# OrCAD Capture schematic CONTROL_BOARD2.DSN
size A4; title: CONTROL BOARD2; rev: 1.0; note: ELECTRONIC CAD 2024.06.03

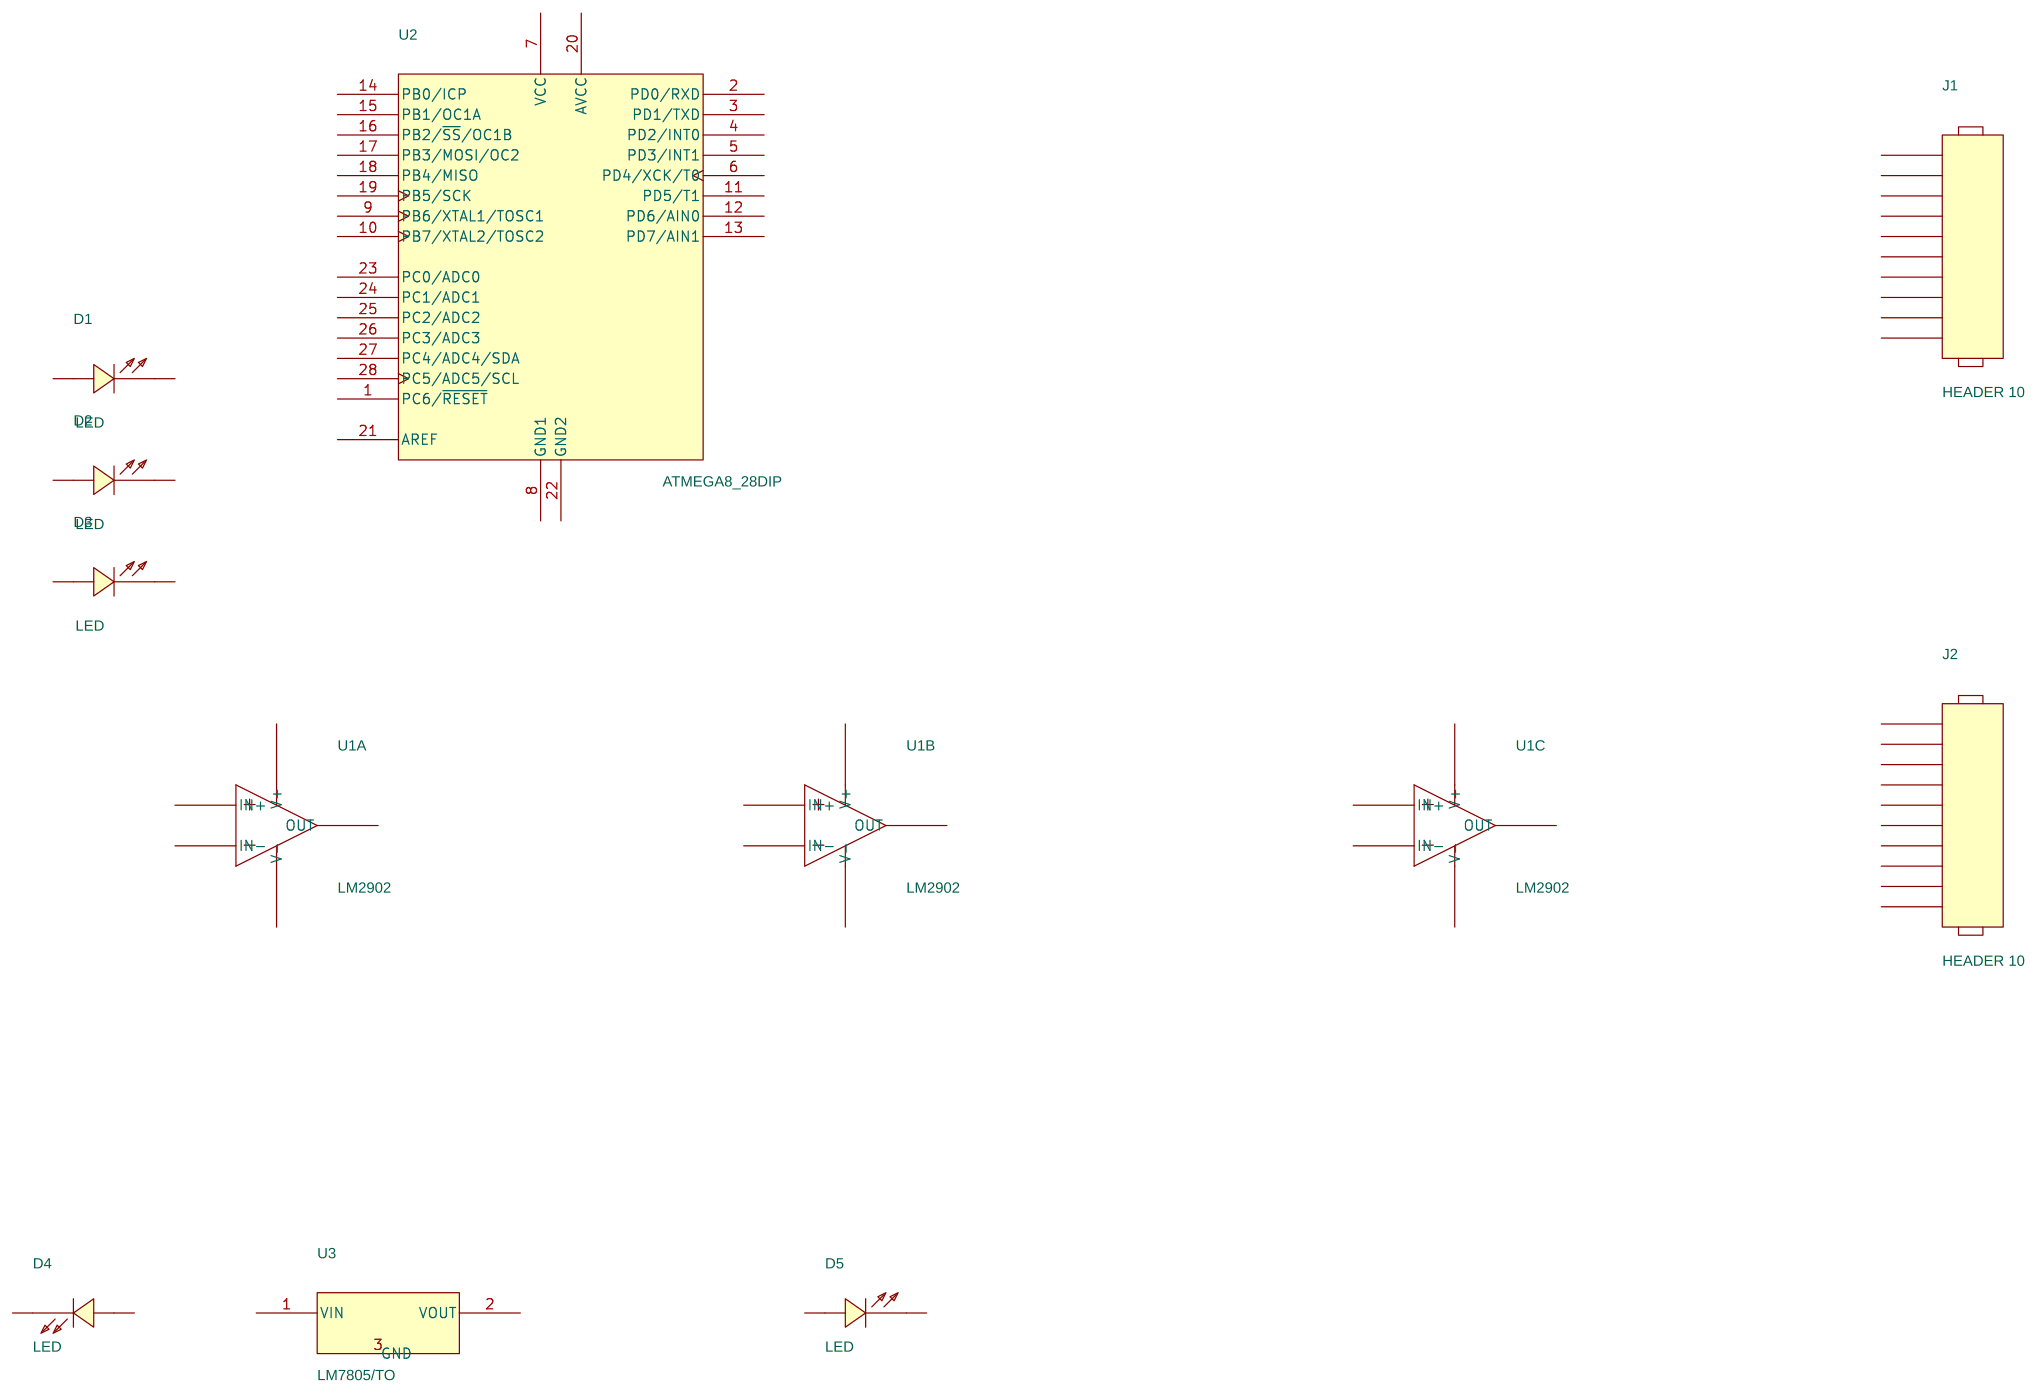
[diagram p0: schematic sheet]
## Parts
D1  LED
D2  LED
D3  LED
D4  LED
D5  LED
J1  HEADER 10
J2  HEADER 10
U1  LM2902  (sections A,B,C)
U2  ATMEGA8_28DIP
U3  LM7805/TO

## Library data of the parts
D1-D5 = LED
J1 J2 = HEADER_10
U1 = LM2902_0
U2 = ATMEGA8_28DIP
U3 = LM7805_TO

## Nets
AVCC: U2.20(AVCC)
GND: U3.3(GND)
GND1: U2.8(GND1)
GND2: U2.22(GND2)
VCC: U2.7(VCC)
V+: U1.4(V+)
V-: U1.11(V-)

Not connected (* = marked no-connect by the designer): D1 1(CATHODE) 2(ANODE); D2 1(CATHODE) 2(ANODE); D3 1(CATHODE) 2(ANODE); D4 1(CATHODE) 2(ANODE); D5 1(CATHODE) 2(ANODE); J1 1 2 3 4 5 6 7 8 9 10; J2 1 2 3 4 5 6 7 8 9 10; U1 1(OUT) 2(IN-) 3(IN+) 5(IN+) 6(IN-) 7(OUT) 8(OUT) 9(IN-) 10(IN+); U2 1(PC6/~{RESET}) 2(PD0/RXD) 3(PD1/TXD) 4(PD2/INT0) 5(PD3/INT1) 6(PD4/XCK/T0) 9(PB6/XTAL1/TOSC1) 10(PB7/XTAL2/TOSC2) 11(PD5/T1) 12(PD6/AIN0) 13(PD7/AIN1) 14(PB0/ICP) 15(PB1/OC1A) 16(PB2/~{SS}/OC1B) 17(PB3/MOSI/OC2) 18(PB4/MISO) 19(PB5/SCK) 21(AREF) 23(PC0/ADC0) 24(PC1/ADC1) 25(PC2/ADC2) 26(PC3/ADC3) 27(PC4/ADC4/SDA) 28(PC5/ADC5/SCL); U3 1(VIN) 2(VOUT)
